VERSION 5.7 ;
  NOWIREEXTENSIONATPIN ON ;
  DIVIDERCHAR "/" ;
  BUSBITCHARS "[]" ;
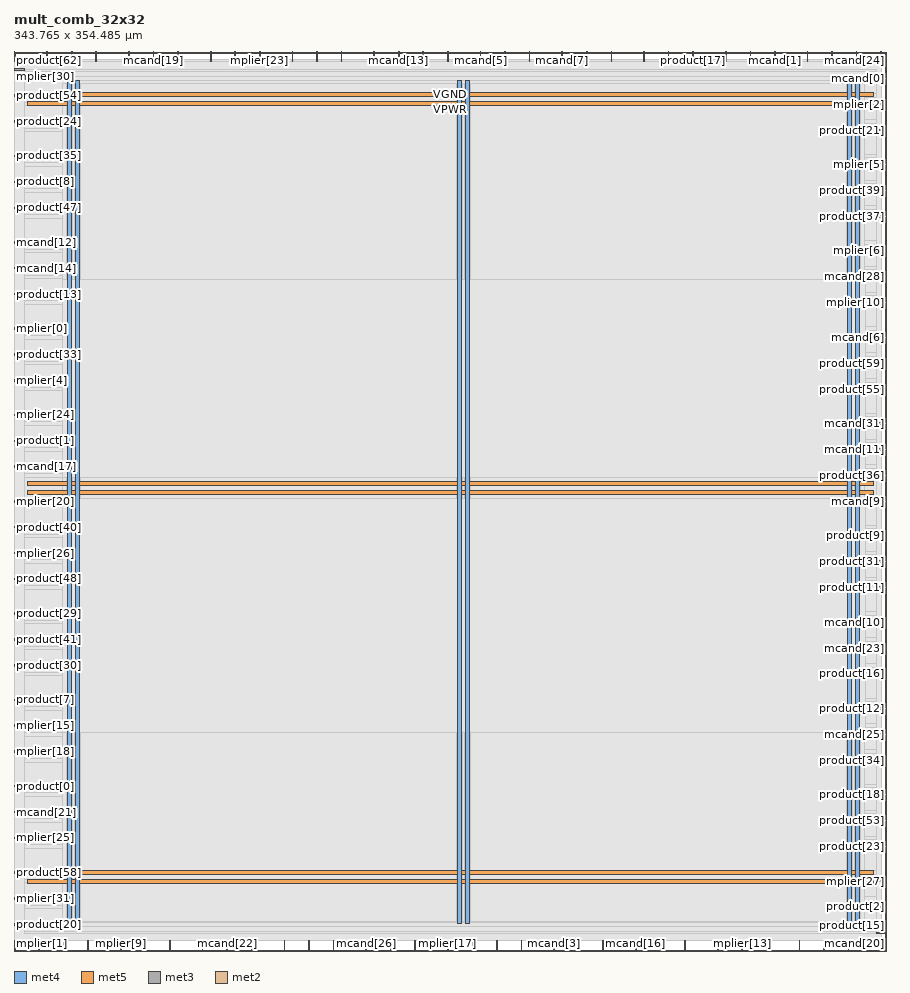
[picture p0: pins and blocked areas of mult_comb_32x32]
MACRO mult_comb_32x32
  CLASS BLOCK ;
  FOREIGN mult_comb_32x32 ;
  ORIGIN 0.000 0.000 ;
  SIZE 343.765 BY 354.485 ;
  PIN VGND
    DIRECTION INOUT ;
    USE GROUND ;
    PORT
      LAYER met4 ;
        RECT 24.340 10.640 25.940 342.960 ;
    END
    PORT
      LAYER met4 ;
        RECT 177.940 10.640 179.540 342.960 ;
    END
    PORT
      LAYER met4 ;
        RECT 331.540 10.640 333.140 342.960 ;
    END
    PORT
      LAYER met5 ;
        RECT 5.280 30.030 338.340 31.630 ;
    END
    PORT
      LAYER met5 ;
        RECT 5.280 183.210 338.340 184.810 ;
    END
    PORT
      LAYER met5 ;
        RECT 5.280 336.390 338.340 337.990 ;
    END
  END VGND
  PIN VPWR
    DIRECTION INOUT ;
    USE POWER ;
    PORT
      LAYER met4 ;
        RECT 21.040 10.640 22.640 342.960 ;
    END
    PORT
      LAYER met4 ;
        RECT 174.640 10.640 176.240 342.960 ;
    END
    PORT
      LAYER met4 ;
        RECT 328.240 10.640 329.840 342.960 ;
    END
    PORT
      LAYER met5 ;
        RECT 5.280 26.730 338.340 28.330 ;
    END
    PORT
      LAYER met5 ;
        RECT 5.280 179.910 338.340 181.510 ;
    END
    PORT
      LAYER met5 ;
        RECT 5.280 333.090 338.340 334.690 ;
    END
  END VPWR
  PIN mcand[0]
    DIRECTION INPUT ;
    USE SIGNAL ;
    ANTENNAGATEAREA 0.426000 ;
    PORT
      LAYER met3 ;
        RECT 339.765 343.440 343.765 344.040 ;
    END
  END mcand[0]
  PIN mcand[10]
    DIRECTION INPUT ;
    USE SIGNAL ;
    ANTENNAGATEAREA 0.159000 ;
    PORT
      LAYER met3 ;
        RECT 339.765 129.240 343.765 129.840 ;
    END
  END mcand[10]
  PIN mcand[11]
    DIRECTION INPUT ;
    USE SIGNAL ;
    ANTENNAGATEAREA 0.247500 ;
    PORT
      LAYER met3 ;
        RECT 339.765 197.240 343.765 197.840 ;
    END
  END mcand[11]
  PIN mcand[12]
    DIRECTION INPUT ;
    USE SIGNAL ;
    ANTENNAGATEAREA 0.213000 ;
    PORT
      LAYER met3 ;
        RECT 0.000 278.840 4.000 279.440 ;
    END
  END mcand[12]
  PIN mcand[13]
    DIRECTION INPUT ;
    USE SIGNAL ;
    ANTENNAGATEAREA 0.247500 ;
    PORT
      LAYER met2 ;
        RECT 151.430 350.485 151.710 354.485 ;
    END
  END mcand[13]
  PIN mcand[14]
    DIRECTION INPUT ;
    USE SIGNAL ;
    ANTENNAGATEAREA 0.247500 ;
    PORT
      LAYER met3 ;
        RECT 0.000 268.640 4.000 269.240 ;
    END
  END mcand[14]
  PIN mcand[15]
    DIRECTION INPUT ;
    USE SIGNAL ;
    ANTENNAGATEAREA 0.159000 ;
    PORT
      LAYER met2 ;
        RECT 161.090 350.485 161.370 354.485 ;
    END
  END mcand[15]
  PIN mcand[16]
    DIRECTION INPUT ;
    USE SIGNAL ;
    ANTENNAGATEAREA 0.213000 ;
    PORT
      LAYER met2 ;
        RECT 244.810 0.000 245.090 4.000 ;
    END
  END mcand[16]
  PIN mcand[17]
    DIRECTION INPUT ;
    USE SIGNAL ;
    ANTENNAGATEAREA 0.213000 ;
    PORT
      LAYER met3 ;
        RECT 0.000 190.440 4.000 191.040 ;
    END
  END mcand[17]
  PIN mcand[18]
    DIRECTION INPUT ;
    USE SIGNAL ;
    ANTENNAGATEAREA 0.247500 ;
    PORT
      LAYER met2 ;
        RECT 289.890 350.485 290.170 354.485 ;
    END
  END mcand[18]
  PIN mcand[19]
    DIRECTION INPUT ;
    USE SIGNAL ;
    ANTENNAGATEAREA 0.247500 ;
    PORT
      LAYER met2 ;
        RECT 54.830 350.485 55.110 354.485 ;
    END
  END mcand[19]
  PIN mcand[1]
    DIRECTION INPUT ;
    USE SIGNAL ;
    ANTENNAGATEAREA 0.159000 ;
    PORT
      LAYER met2 ;
        RECT 299.550 350.485 299.830 354.485 ;
    END
  END mcand[1]
  PIN mcand[20]
    DIRECTION INPUT ;
    USE SIGNAL ;
    ANTENNAGATEAREA 0.247500 ;
    PORT
      LAYER met2 ;
        RECT 341.410 0.000 341.690 4.000 ;
    END
  END mcand[20]
  PIN mcand[21]
    DIRECTION INPUT ;
    USE SIGNAL ;
    ANTENNAGATEAREA 0.213000 ;
    PORT
      LAYER met3 ;
        RECT 0.000 54.440 4.000 55.040 ;
    END
  END mcand[21]
  PIN mcand[22]
    DIRECTION INPUT ;
    USE SIGNAL ;
    ANTENNAGATEAREA 0.213000 ;
    PORT
      LAYER met2 ;
        RECT 83.810 0.000 84.090 4.000 ;
    END
  END mcand[22]
  PIN mcand[23]
    DIRECTION INPUT ;
    USE SIGNAL ;
    ANTENNAGATEAREA 0.213000 ;
    PORT
      LAYER met3 ;
        RECT 339.765 119.040 343.765 119.640 ;
    END
  END mcand[23]
  PIN mcand[24]
    DIRECTION INPUT ;
    USE SIGNAL ;
    ANTENNAGATEAREA 0.247500 ;
    PORT
      LAYER met2 ;
        RECT 341.410 350.485 341.690 354.485 ;
    END
  END mcand[24]
  PIN mcand[25]
    DIRECTION INPUT ;
    USE SIGNAL ;
    ANTENNAGATEAREA 0.159000 ;
    PORT
      LAYER met3 ;
        RECT 339.765 85.040 343.765 85.640 ;
    END
  END mcand[25]
  PIN mcand[26]
    DIRECTION INPUT ;
    USE SIGNAL ;
    ANTENNAGATEAREA 0.247500 ;
    PORT
      LAYER met2 ;
        RECT 138.550 0.000 138.830 4.000 ;
    END
  END mcand[26]
  PIN mcand[27]
    DIRECTION INPUT ;
    USE SIGNAL ;
    ANTENNAGATEAREA 0.159000 ;
    PORT
      LAYER met2 ;
        RECT 141.770 350.485 142.050 354.485 ;
    END
  END mcand[27]
  PIN mcand[28]
    DIRECTION INPUT ;
    USE SIGNAL ;
    ANTENNAGATEAREA 0.213000 ;
    PORT
      LAYER met3 ;
        RECT 339.765 265.240 343.765 265.840 ;
    END
  END mcand[28]
  PIN mcand[29]
    DIRECTION INPUT ;
    USE SIGNAL ;
    ANTENNAGATEAREA 0.247500 ;
    PORT
      LAYER met2 ;
        RECT 199.730 0.000 200.010 4.000 ;
    END
  END mcand[29]
  PIN mcand[2]
    DIRECTION INPUT ;
    USE SIGNAL ;
    ANTENNAGATEAREA 0.196500 ;
    PORT
      LAYER met2 ;
        RECT 93.470 0.000 93.750 4.000 ;
    END
  END mcand[2]
  PIN mcand[30]
    DIRECTION INPUT ;
    USE SIGNAL ;
    ANTENNAGATEAREA 0.196500 ;
    PORT
      LAYER met2 ;
        RECT 77.370 350.485 77.650 354.485 ;
    END
  END mcand[30]
  PIN mcand[31]
    DIRECTION INPUT ;
    USE SIGNAL ;
    ANTENNAGATEAREA 0.196500 ;
    PORT
      LAYER met3 ;
        RECT 339.765 207.440 343.765 208.040 ;
    END
  END mcand[31]
  PIN mcand[3]
    DIRECTION INPUT ;
    USE SIGNAL ;
    ANTENNAGATEAREA 0.196500 ;
    PORT
      LAYER met2 ;
        RECT 212.610 0.000 212.890 4.000 ;
    END
  END mcand[3]
  PIN mcand[4]
    DIRECTION INPUT ;
    USE SIGNAL ;
    ANTENNAGATEAREA 0.426000 ;
    PORT
      LAYER met2 ;
        RECT 322.090 350.485 322.370 354.485 ;
    END
  END mcand[4]
  PIN mcand[5]
    DIRECTION INPUT ;
    USE SIGNAL ;
    ANTENNAGATEAREA 0.213000 ;
    PORT
      LAYER met2 ;
        RECT 183.630 350.485 183.910 354.485 ;
    END
  END mcand[5]
  PIN mcand[6]
    DIRECTION INPUT ;
    USE SIGNAL ;
    ANTENNAGATEAREA 0.213000 ;
    PORT
      LAYER met3 ;
        RECT 339.765 241.440 343.765 242.040 ;
    END
  END mcand[6]
  PIN mcand[7]
    DIRECTION INPUT ;
    USE SIGNAL ;
    ANTENNAGATEAREA 0.213000 ;
    PORT
      LAYER met2 ;
        RECT 215.830 350.485 216.110 354.485 ;
    END
  END mcand[7]
  PIN mcand[8]
    DIRECTION INPUT ;
    USE SIGNAL ;
    ANTENNAGATEAREA 0.247500 ;
    PORT
      LAYER met2 ;
        RECT 328.530 0.000 328.810 4.000 ;
    END
  END mcand[8]
  PIN mcand[9]
    DIRECTION INPUT ;
    USE SIGNAL ;
    ANTENNAGATEAREA 0.213000 ;
    PORT
      LAYER met3 ;
        RECT 339.765 176.840 343.765 177.440 ;
    END
  END mcand[9]
  PIN mplier[0]
    DIRECTION INPUT ;
    USE SIGNAL ;
    ANTENNAGATEAREA 0.213000 ;
    PORT
      LAYER met3 ;
        RECT 0.000 244.840 4.000 245.440 ;
    END
  END mplier[0]
  PIN mplier[10]
    DIRECTION INPUT ;
    USE SIGNAL ;
    ANTENNAGATEAREA 0.247500 ;
    PORT
      LAYER met3 ;
        RECT 339.765 255.040 343.765 255.640 ;
    END
  END mplier[10]
  PIN mplier[11]
    DIRECTION INPUT ;
    USE SIGNAL ;
    ANTENNAGATEAREA 0.213000 ;
    PORT
      LAYER met2 ;
        RECT 148.210 0.000 148.490 4.000 ;
    END
  END mplier[11]
  PIN mplier[12]
    DIRECTION INPUT ;
    USE SIGNAL ;
    ANTENNAGATEAREA 0.213000 ;
    PORT
      LAYER met2 ;
        RECT 331.750 350.485 332.030 354.485 ;
    END
  END mplier[12]
  PIN mplier[13]
    DIRECTION INPUT ;
    USE SIGNAL ;
    ANTENNAGATEAREA 0.247500 ;
    PORT
      LAYER met2 ;
        RECT 286.670 0.000 286.950 4.000 ;
    END
  END mplier[13]
  PIN mplier[14]
    DIRECTION INPUT ;
    USE SIGNAL ;
    ANTENNAGATEAREA 0.213000 ;
    PORT
      LAYER met2 ;
        RECT 264.130 0.000 264.410 4.000 ;
    END
  END mplier[14]
  PIN mplier[15]
    DIRECTION INPUT ;
    USE SIGNAL ;
    ANTENNAGATEAREA 0.196500 ;
    PORT
      LAYER met3 ;
        RECT 0.000 88.440 4.000 89.040 ;
    END
  END mplier[15]
  PIN mplier[16]
    DIRECTION INPUT ;
    USE SIGNAL ;
    ANTENNAGATEAREA 0.213000 ;
    PORT
      LAYER met2 ;
        RECT 106.350 0.000 106.630 4.000 ;
    END
  END mplier[16]
  PIN mplier[17]
    DIRECTION INPUT ;
    USE SIGNAL ;
    ANTENNAGATEAREA 0.159000 ;
    PORT
      LAYER met2 ;
        RECT 170.750 0.000 171.030 4.000 ;
    END
  END mplier[17]
  PIN mplier[18]
    DIRECTION INPUT ;
    USE SIGNAL ;
    ANTENNAGATEAREA 0.213000 ;
    PORT
      LAYER met3 ;
        RECT 0.000 78.240 4.000 78.840 ;
    END
  END mplier[18]
  PIN mplier[19]
    DIRECTION INPUT ;
    USE SIGNAL ;
    ANTENNAGATEAREA 0.247500 ;
    PORT
      LAYER met2 ;
        RECT 193.290 350.485 193.570 354.485 ;
    END
  END mplier[19]
  PIN mplier[1]
    DIRECTION INPUT ;
    USE SIGNAL ;
    ANTENNAGATEAREA 0.159000 ;
    PORT
      LAYER met2 ;
        RECT 9.750 0.000 10.030 4.000 ;
    END
  END mplier[1]
  PIN mplier[20]
    DIRECTION INPUT ;
    USE SIGNAL ;
    ANTENNAGATEAREA 0.213000 ;
    PORT
      LAYER met3 ;
        RECT 0.000 176.840 4.000 177.440 ;
    END
  END mplier[20]
  PIN mplier[21]
    DIRECTION INPUT ;
    USE SIGNAL ;
    ANTENNAGATEAREA 0.213000 ;
    PORT
      LAYER met2 ;
        RECT 32.290 350.485 32.570 354.485 ;
    END
  END mplier[21]
  PIN mplier[22]
    DIRECTION INPUT ;
    USE SIGNAL ;
    ANTENNAGATEAREA 0.213000 ;
    PORT
      LAYER met2 ;
        RECT 235.150 350.485 235.430 354.485 ;
    END
  END mplier[22]
  PIN mplier[23]
    DIRECTION INPUT ;
    USE SIGNAL ;
    ANTENNAGATEAREA 0.159000 ;
    PORT
      LAYER met2 ;
        RECT 96.690 350.485 96.970 354.485 ;
    END
  END mplier[23]
  PIN mplier[24]
    DIRECTION INPUT ;
    USE SIGNAL ;
    ANTENNAGATEAREA 0.213000 ;
    PORT
      LAYER met3 ;
        RECT 0.000 210.840 4.000 211.440 ;
    END
  END mplier[24]
  PIN mplier[25]
    DIRECTION INPUT ;
    USE SIGNAL ;
    ANTENNAGATEAREA 0.126000 ;
    PORT
      LAYER met3 ;
        RECT 0.000 44.240 4.000 44.840 ;
    END
  END mplier[25]
  PIN mplier[26]
    DIRECTION INPUT ;
    USE SIGNAL ;
    ANTENNAGATEAREA 0.159000 ;
    PORT
      LAYER met3 ;
        RECT 0.000 156.440 4.000 157.040 ;
    END
  END mplier[26]
  PIN mplier[27]
    DIRECTION INPUT ;
    USE SIGNAL ;
    ANTENNAGATEAREA 0.213000 ;
    PORT
      LAYER met3 ;
        RECT 339.765 27.240 343.765 27.840 ;
    END
  END mplier[27]
  PIN mplier[28]
    DIRECTION INPUT ;
    USE SIGNAL ;
    ANTENNAGATEAREA 0.213000 ;
    PORT
      LAYER met2 ;
        RECT 125.670 0.000 125.950 4.000 ;
    END
  END mplier[28]
  PIN mplier[29]
    DIRECTION INPUT ;
    USE SIGNAL ;
    ANTENNAGATEAREA 0.126000 ;
    PORT
      LAYER met2 ;
        RECT 51.610 0.000 51.890 4.000 ;
    END
  END mplier[29]
  PIN mplier[2]
    DIRECTION INPUT ;
    USE SIGNAL ;
    ANTENNAGATEAREA 0.247500 ;
    PORT
      LAYER met3 ;
        RECT 339.765 333.240 343.765 333.840 ;
    END
  END mplier[2]
  PIN mplier[30]
    DIRECTION INPUT ;
    USE SIGNAL ;
    ANTENNAGATEAREA 0.159000 ;
    PORT
      LAYER met3 ;
        RECT 0.000 346.840 4.000 347.440 ;
    END
  END mplier[30]
  PIN mplier[31]
    DIRECTION INPUT ;
    USE SIGNAL ;
    ANTENNAGATEAREA 0.213000 ;
    PORT
      LAYER met3 ;
        RECT 0.000 20.440 4.000 21.040 ;
    END
  END mplier[31]
  PIN mplier[3]
    DIRECTION INPUT ;
    USE SIGNAL ;
    ANTENNAGATEAREA 0.213000 ;
    PORT
      LAYER met2 ;
        RECT 87.030 350.485 87.310 354.485 ;
    END
  END mplier[3]
  PIN mplier[4]
    DIRECTION INPUT ;
    USE SIGNAL ;
    ANTENNAGATEAREA 0.159000 ;
    PORT
      LAYER met3 ;
        RECT 0.000 224.440 4.000 225.040 ;
    END
  END mplier[4]
  PIN mplier[5]
    DIRECTION INPUT ;
    USE SIGNAL ;
    ANTENNAGATEAREA 0.159000 ;
    PORT
      LAYER met3 ;
        RECT 339.765 309.440 343.765 310.040 ;
    END
  END mplier[5]
  PIN mplier[6]
    DIRECTION INPUT ;
    USE SIGNAL ;
    ANTENNAGATEAREA 0.213000 ;
    PORT
      LAYER met3 ;
        RECT 339.765 275.440 343.765 276.040 ;
    END
  END mplier[6]
  PIN mplier[7]
    DIRECTION INPUT ;
    USE SIGNAL ;
    ANTENNAGATEAREA 0.247500 ;
    PORT
      LAYER met2 ;
        RECT 22.630 350.485 22.910 354.485 ;
    END
  END mplier[7]
  PIN mplier[8]
    DIRECTION INPUT ;
    USE SIGNAL ;
    ANTENNAGATEAREA 0.159000 ;
    PORT
      LAYER met2 ;
        RECT 45.170 350.485 45.450 354.485 ;
    END
  END mplier[8]
  PIN mplier[9]
    DIRECTION INPUT ;
    USE SIGNAL ;
    ANTENNAGATEAREA 0.213000 ;
    PORT
      LAYER met2 ;
        RECT 41.950 0.000 42.230 4.000 ;
    END
  END mplier[9]
  PIN product[0]
    DIRECTION OUTPUT TRISTATE ;
    USE SIGNAL ;
    ANTENNADIFFAREA 0.795200 ;
    PORT
      LAYER met3 ;
        RECT 0.000 64.640 4.000 65.240 ;
    END
  END product[0]
  PIN product[10]
    DIRECTION OUTPUT TRISTATE ;
    USE SIGNAL ;
    ANTENNADIFFAREA 0.795200 ;
    PORT
      LAYER met2 ;
        RECT 119.230 350.485 119.510 354.485 ;
    END
  END product[10]
  PIN product[11]
    DIRECTION OUTPUT TRISTATE ;
    USE SIGNAL ;
    ANTENNADIFFAREA 0.795200 ;
    PORT
      LAYER met3 ;
        RECT 339.765 142.840 343.765 143.440 ;
    END
  END product[11]
  PIN product[12]
    DIRECTION OUTPUT TRISTATE ;
    USE SIGNAL ;
    ANTENNADIFFAREA 0.795200 ;
    PORT
      LAYER met3 ;
        RECT 339.765 95.240 343.765 95.840 ;
    END
  END product[12]
  PIN product[13]
    DIRECTION OUTPUT TRISTATE ;
    USE SIGNAL ;
    ANTENNADIFFAREA 0.795200 ;
    PORT
      LAYER met3 ;
        RECT 0.000 258.440 4.000 259.040 ;
    END
  END product[13]
  PIN product[14]
    DIRECTION OUTPUT TRISTATE ;
    USE SIGNAL ;
    ANTENNADIFFAREA 0.795200 ;
    PORT
      LAYER met2 ;
        RECT 128.890 350.485 129.170 354.485 ;
    END
  END product[14]
  PIN product[15]
    DIRECTION OUTPUT TRISTATE ;
    USE SIGNAL ;
    ANTENNADIFFAREA 0.445500 ;
    PORT
      LAYER met3 ;
        RECT 339.765 6.840 343.765 7.440 ;
    END
  END product[15]
  PIN product[16]
    DIRECTION OUTPUT TRISTATE ;
    USE SIGNAL ;
    ANTENNADIFFAREA 0.445500 ;
    PORT
      LAYER met3 ;
        RECT 339.765 108.840 343.765 109.440 ;
    END
  END product[16]
  PIN product[17]
    DIRECTION OUTPUT TRISTATE ;
    USE SIGNAL ;
    ANTENNADIFFAREA 0.795200 ;
    PORT
      LAYER met2 ;
        RECT 267.350 350.485 267.630 354.485 ;
    END
  END product[17]
  PIN product[18]
    DIRECTION OUTPUT TRISTATE ;
    USE SIGNAL ;
    ANTENNADIFFAREA 0.795200 ;
    PORT
      LAYER met3 ;
        RECT 339.765 61.240 343.765 61.840 ;
    END
  END product[18]
  PIN product[19]
    DIRECTION OUTPUT TRISTATE ;
    USE SIGNAL ;
    ANTENNADIFFAREA 0.795200 ;
    PORT
      LAYER met2 ;
        RECT 296.330 0.000 296.610 4.000 ;
    END
  END product[19]
  PIN product[1]
    DIRECTION OUTPUT TRISTATE ;
    USE SIGNAL ;
    ANTENNADIFFAREA 0.795200 ;
    PORT
      LAYER met3 ;
        RECT 0.000 200.640 4.000 201.240 ;
    END
  END product[1]
  PIN product[20]
    DIRECTION OUTPUT TRISTATE ;
    USE SIGNAL ;
    ANTENNADIFFAREA 0.795200 ;
    PORT
      LAYER met3 ;
        RECT 0.000 10.240 4.000 10.840 ;
    END
  END product[20]
  PIN product[21]
    DIRECTION OUTPUT TRISTATE ;
    USE SIGNAL ;
    ANTENNADIFFAREA 0.795200 ;
    PORT
      LAYER met3 ;
        RECT 339.765 323.040 343.765 323.640 ;
    END
  END product[21]
  PIN product[22]
    DIRECTION OUTPUT TRISTATE ;
    USE SIGNAL ;
    ANTENNADIFFAREA 0.795200 ;
    PORT
      LAYER met2 ;
        RECT 74.150 0.000 74.430 4.000 ;
    END
  END product[22]
  PIN product[23]
    DIRECTION OUTPUT TRISTATE ;
    USE SIGNAL ;
    ANTENNADIFFAREA 0.795200 ;
    PORT
      LAYER met3 ;
        RECT 339.765 40.840 343.765 41.440 ;
    END
  END product[23]
  PIN product[24]
    DIRECTION OUTPUT TRISTATE ;
    USE SIGNAL ;
    ANTENNADIFFAREA 0.795200 ;
    PORT
      LAYER met3 ;
        RECT 0.000 326.440 4.000 327.040 ;
    END
  END product[24]
  PIN product[25]
    DIRECTION OUTPUT TRISTATE ;
    USE SIGNAL ;
    ANTENNADIFFAREA 0.795200 ;
    PORT
      LAYER met2 ;
        RECT 318.870 0.000 319.150 4.000 ;
    END
  END product[25]
  PIN product[26]
    DIRECTION OUTPUT TRISTATE ;
    USE SIGNAL ;
    ANTENNADIFFAREA 0.795200 ;
    PORT
      LAYER met2 ;
        RECT 170.750 350.485 171.030 354.485 ;
    END
  END product[26]
  PIN product[27]
    DIRECTION OUTPUT TRISTATE ;
    USE SIGNAL ;
    ANTENNADIFFAREA 0.795200 ;
    PORT
      LAYER met2 ;
        RECT 254.470 0.000 254.750 4.000 ;
    END
  END product[27]
  PIN product[28]
    DIRECTION OUTPUT TRISTATE ;
    USE SIGNAL ;
    ANTENNADIFFAREA 0.795200 ;
    PORT
      LAYER met2 ;
        RECT 29.070 0.000 29.350 4.000 ;
    END
  END product[28]
  PIN product[29]
    DIRECTION OUTPUT TRISTATE ;
    USE SIGNAL ;
    ANTENNADIFFAREA 0.795200 ;
    PORT
      LAYER met3 ;
        RECT 0.000 132.640 4.000 133.240 ;
    END
  END product[29]
  PIN product[2]
    DIRECTION OUTPUT TRISTATE ;
    USE SIGNAL ;
    ANTENNADIFFAREA 0.445500 ;
    PORT
      LAYER met3 ;
        RECT 339.765 17.040 343.765 17.640 ;
    END
  END product[2]
  PIN product[30]
    DIRECTION OUTPUT TRISTATE ;
    USE SIGNAL ;
    ANTENNADIFFAREA 0.795200 ;
    PORT
      LAYER met3 ;
        RECT 0.000 112.240 4.000 112.840 ;
    END
  END product[30]
  PIN product[31]
    DIRECTION OUTPUT TRISTATE ;
    USE SIGNAL ;
    ANTENNADIFFAREA 0.445500 ;
    PORT
      LAYER met3 ;
        RECT 339.765 153.040 343.765 153.640 ;
    END
  END product[31]
  PIN product[32]
    DIRECTION OUTPUT TRISTATE ;
    USE SIGNAL ;
    ANTENNADIFFAREA 0.795200 ;
    PORT
      LAYER met2 ;
        RECT 277.010 0.000 277.290 4.000 ;
    END
  END product[32]
  PIN product[33]
    DIRECTION OUTPUT TRISTATE ;
    USE SIGNAL ;
    ANTENNADIFFAREA 0.795200 ;
    PORT
      LAYER met3 ;
        RECT 0.000 234.640 4.000 235.240 ;
    END
  END product[33]
  PIN product[34]
    DIRECTION OUTPUT TRISTATE ;
    USE SIGNAL ;
    ANTENNADIFFAREA 0.795200 ;
    PORT
      LAYER met3 ;
        RECT 339.765 74.840 343.765 75.440 ;
    END
  END product[34]
  PIN product[35]
    DIRECTION OUTPUT TRISTATE ;
    USE SIGNAL ;
    ANTENNADIFFAREA 0.795200 ;
    PORT
      LAYER met3 ;
        RECT 0.000 312.840 4.000 313.440 ;
    END
  END product[35]
  PIN product[36]
    DIRECTION OUTPUT TRISTATE ;
    USE SIGNAL ;
    ANTENNADIFFAREA 0.445500 ;
    PORT
      LAYER met3 ;
        RECT 339.765 187.040 343.765 187.640 ;
    END
  END product[36]
  PIN product[37]
    DIRECTION OUTPUT TRISTATE ;
    USE SIGNAL ;
    ANTENNADIFFAREA 0.445500 ;
    PORT
      LAYER met3 ;
        RECT 339.765 289.040 343.765 289.640 ;
    END
  END product[37]
  PIN product[38]
    DIRECTION OUTPUT TRISTATE ;
    USE SIGNAL ;
    ANTENNADIFFAREA 0.795200 ;
    PORT
      LAYER met2 ;
        RECT 309.210 0.000 309.490 4.000 ;
    END
  END product[38]
  PIN product[39]
    DIRECTION OUTPUT TRISTATE ;
    USE SIGNAL ;
    ANTENNADIFFAREA 0.445500 ;
    PORT
      LAYER met3 ;
        RECT 339.765 299.240 343.765 299.840 ;
    END
  END product[39]
  PIN product[3]
    DIRECTION OUTPUT TRISTATE ;
    USE SIGNAL ;
    ANTENNADIFFAREA 0.795200 ;
    PORT
      LAYER met2 ;
        RECT 180.410 0.000 180.690 4.000 ;
    END
  END product[3]
  PIN product[40]
    DIRECTION OUTPUT TRISTATE ;
    USE SIGNAL ;
    ANTENNADIFFAREA 0.795200 ;
    PORT
      LAYER met3 ;
        RECT 0.000 166.640 4.000 167.240 ;
    END
  END product[40]
  PIN product[41]
    DIRECTION OUTPUT TRISTATE ;
    USE SIGNAL ;
    ANTENNADIFFAREA 0.795200 ;
    PORT
      LAYER met3 ;
        RECT 0.000 122.440 4.000 123.040 ;
    END
  END product[41]
  PIN product[42]
    DIRECTION OUTPUT TRISTATE ;
    USE SIGNAL ;
    ANTENNADIFFAREA 0.795200 ;
    PORT
      LAYER met2 ;
        RECT 0.090 0.000 0.370 4.000 ;
    END
  END product[42]
  PIN product[43]
    DIRECTION OUTPUT TRISTATE ;
    USE SIGNAL ;
    ANTENNADIFFAREA 0.795200 ;
    PORT
      LAYER met2 ;
        RECT 222.270 0.000 222.550 4.000 ;
    END
  END product[43]
  PIN product[44]
    DIRECTION OUTPUT TRISTATE ;
    USE SIGNAL ;
    ANTENNADIFFAREA 0.795200 ;
    PORT
      LAYER met2 ;
        RECT 0.090 350.485 0.370 354.485 ;
    END
  END product[44]
  PIN product[45]
    DIRECTION OUTPUT TRISTATE ;
    USE SIGNAL ;
    ANTENNADIFFAREA 0.795200 ;
    PORT
      LAYER met2 ;
        RECT 109.570 350.485 109.850 354.485 ;
    END
  END product[45]
  PIN product[46]
    DIRECTION OUTPUT TRISTATE ;
    USE SIGNAL ;
    ANTENNADIFFAREA 0.795200 ;
    PORT
      LAYER met2 ;
        RECT 225.490 350.485 225.770 354.485 ;
    END
  END product[46]
  PIN product[47]
    DIRECTION OUTPUT TRISTATE ;
    USE SIGNAL ;
    ANTENNADIFFAREA 0.795200 ;
    PORT
      LAYER met3 ;
        RECT 0.000 292.440 4.000 293.040 ;
    END
  END product[47]
  PIN product[48]
    DIRECTION OUTPUT TRISTATE ;
    USE SIGNAL ;
    ANTENNADIFFAREA 0.795200 ;
    PORT
      LAYER met3 ;
        RECT 0.000 146.240 4.000 146.840 ;
    END
  END product[48]
  PIN product[49]
    DIRECTION OUTPUT TRISTATE ;
    USE SIGNAL ;
    ANTENNADIFFAREA 0.795200 ;
    PORT
      LAYER met2 ;
        RECT 19.410 0.000 19.690 4.000 ;
    END
  END product[49]
  PIN product[4]
    DIRECTION OUTPUT TRISTATE ;
    USE SIGNAL ;
    ANTENNADIFFAREA 0.795200 ;
    PORT
      LAYER met2 ;
        RECT 280.230 350.485 280.510 354.485 ;
    END
  END product[4]
  PIN product[50]
    DIRECTION OUTPUT TRISTATE ;
    USE SIGNAL ;
    ANTENNADIFFAREA 0.445500 ;
    PORT
      LAYER met2 ;
        RECT 202.950 350.485 203.230 354.485 ;
    END
  END product[50]
  PIN product[51]
    DIRECTION OUTPUT TRISTATE ;
    USE SIGNAL ;
    ANTENNADIFFAREA 0.795200 ;
    PORT
      LAYER met2 ;
        RECT 157.870 0.000 158.150 4.000 ;
    END
  END product[51]
  PIN product[52]
    DIRECTION OUTPUT TRISTATE ;
    USE SIGNAL ;
    ANTENNADIFFAREA 0.795200 ;
    PORT
      LAYER met2 ;
        RECT 312.430 350.485 312.710 354.485 ;
    END
  END product[52]
  PIN product[53]
    DIRECTION OUTPUT TRISTATE ;
    USE SIGNAL ;
    ANTENNADIFFAREA 0.445500 ;
    PORT
      LAYER met3 ;
        RECT 339.765 51.040 343.765 51.640 ;
    END
  END product[53]
  PIN product[54]
    DIRECTION OUTPUT TRISTATE ;
    USE SIGNAL ;
    ANTENNADIFFAREA 0.795200 ;
    PORT
      LAYER met3 ;
        RECT 0.000 336.640 4.000 337.240 ;
    END
  END product[54]
  PIN product[55]
    DIRECTION OUTPUT TRISTATE ;
    USE SIGNAL ;
    ANTENNADIFFAREA 0.445500 ;
    PORT
      LAYER met3 ;
        RECT 339.765 221.040 343.765 221.640 ;
    END
  END product[55]
  PIN product[56]
    DIRECTION OUTPUT TRISTATE ;
    USE SIGNAL ;
    ANTENNADIFFAREA 0.795200 ;
    PORT
      LAYER met2 ;
        RECT 61.270 0.000 61.550 4.000 ;
    END
  END product[56]
  PIN product[57]
    DIRECTION OUTPUT TRISTATE ;
    USE SIGNAL ;
    ANTENNADIFFAREA 0.795200 ;
    PORT
      LAYER met2 ;
        RECT 116.010 0.000 116.290 4.000 ;
    END
  END product[57]
  PIN product[58]
    DIRECTION OUTPUT TRISTATE ;
    USE SIGNAL ;
    ANTENNADIFFAREA 0.795200 ;
    PORT
      LAYER met3 ;
        RECT 0.000 30.640 4.000 31.240 ;
    END
  END product[58]
  PIN product[59]
    DIRECTION OUTPUT TRISTATE ;
    USE SIGNAL ;
    ANTENNADIFFAREA 0.445500 ;
    PORT
      LAYER met3 ;
        RECT 339.765 231.240 343.765 231.840 ;
    END
  END product[59]
  PIN product[5]
    DIRECTION OUTPUT TRISTATE ;
    USE SIGNAL ;
    ANTENNADIFFAREA 0.795200 ;
    PORT
      LAYER met2 ;
        RECT 190.070 0.000 190.350 4.000 ;
    END
  END product[5]
  PIN product[60]
    DIRECTION OUTPUT TRISTATE ;
    USE SIGNAL ;
    ANTENNADIFFAREA 0.445500 ;
    PORT
      LAYER met2 ;
        RECT 257.690 350.485 257.970 354.485 ;
    END
  END product[60]
  PIN product[61]
    DIRECTION OUTPUT TRISTATE ;
    USE SIGNAL ;
    ANTENNADIFFAREA 0.795200 ;
    PORT
      LAYER met2 ;
        RECT 248.030 350.485 248.310 354.485 ;
    END
  END product[61]
  PIN product[62]
    DIRECTION OUTPUT TRISTATE ;
    USE SIGNAL ;
    ANTENNADIFFAREA 0.795200 ;
    PORT
      LAYER met2 ;
        RECT 12.970 350.485 13.250 354.485 ;
    END
  END product[62]
  PIN product[63]
    DIRECTION OUTPUT TRISTATE ;
    USE SIGNAL ;
    ANTENNADIFFAREA 0.445500 ;
    PORT
      LAYER met2 ;
        RECT 64.490 350.485 64.770 354.485 ;
    END
  END product[63]
  PIN product[6]
    DIRECTION OUTPUT TRISTATE ;
    USE SIGNAL ;
    ANTENNADIFFAREA 0.795200 ;
    PORT
      LAYER met2 ;
        RECT 231.930 0.000 232.210 4.000 ;
    END
  END product[6]
  PIN product[7]
    DIRECTION OUTPUT TRISTATE ;
    USE SIGNAL ;
    ANTENNADIFFAREA 0.795200 ;
    PORT
      LAYER met3 ;
        RECT 0.000 98.640 4.000 99.240 ;
    END
  END product[7]
  PIN product[8]
    DIRECTION OUTPUT TRISTATE ;
    USE SIGNAL ;
    ANTENNADIFFAREA 0.795200 ;
    PORT
      LAYER met3 ;
        RECT 0.000 302.640 4.000 303.240 ;
    END
  END product[8]
  PIN product[9]
    DIRECTION OUTPUT TRISTATE ;
    USE SIGNAL ;
    ANTENNADIFFAREA 0.445500 ;
    PORT
      LAYER met3 ;
        RECT 339.765 163.240 343.765 163.840 ;
    END
  END product[9]
  OBS
      LAYER li1 ;
        RECT 5.520 10.795 338.100 342.805 ;
      LAYER met1 ;
        RECT 0.070 7.520 341.710 345.740 ;
      LAYER met2 ;
        RECT 0.650 350.205 12.690 351.290 ;
        RECT 13.530 350.205 22.350 351.290 ;
        RECT 23.190 350.205 32.010 351.290 ;
        RECT 32.850 350.205 44.890 351.290 ;
        RECT 45.730 350.205 54.550 351.290 ;
        RECT 55.390 350.205 64.210 351.290 ;
        RECT 65.050 350.205 77.090 351.290 ;
        RECT 77.930 350.205 86.750 351.290 ;
        RECT 87.590 350.205 96.410 351.290 ;
        RECT 97.250 350.205 109.290 351.290 ;
        RECT 110.130 350.205 118.950 351.290 ;
        RECT 119.790 350.205 128.610 351.290 ;
        RECT 129.450 350.205 141.490 351.290 ;
        RECT 142.330 350.205 151.150 351.290 ;
        RECT 151.990 350.205 160.810 351.290 ;
        RECT 161.650 350.205 170.470 351.290 ;
        RECT 171.310 350.205 183.350 351.290 ;
        RECT 184.190 350.205 193.010 351.290 ;
        RECT 193.850 350.205 202.670 351.290 ;
        RECT 203.510 350.205 215.550 351.290 ;
        RECT 216.390 350.205 225.210 351.290 ;
        RECT 226.050 350.205 234.870 351.290 ;
        RECT 235.710 350.205 247.750 351.290 ;
        RECT 248.590 350.205 257.410 351.290 ;
        RECT 258.250 350.205 267.070 351.290 ;
        RECT 267.910 350.205 279.950 351.290 ;
        RECT 280.790 350.205 289.610 351.290 ;
        RECT 290.450 350.205 299.270 351.290 ;
        RECT 300.110 350.205 312.150 351.290 ;
        RECT 312.990 350.205 321.810 351.290 ;
        RECT 322.650 350.205 331.470 351.290 ;
        RECT 332.310 350.205 341.130 351.290 ;
        RECT 0.100 4.280 341.680 350.205 ;
        RECT 0.650 4.000 9.470 4.280 ;
        RECT 10.310 4.000 19.130 4.280 ;
        RECT 19.970 4.000 28.790 4.280 ;
        RECT 29.630 4.000 41.670 4.280 ;
        RECT 42.510 4.000 51.330 4.280 ;
        RECT 52.170 4.000 60.990 4.280 ;
        RECT 61.830 4.000 73.870 4.280 ;
        RECT 74.710 4.000 83.530 4.280 ;
        RECT 84.370 4.000 93.190 4.280 ;
        RECT 94.030 4.000 106.070 4.280 ;
        RECT 106.910 4.000 115.730 4.280 ;
        RECT 116.570 4.000 125.390 4.280 ;
        RECT 126.230 4.000 138.270 4.280 ;
        RECT 139.110 4.000 147.930 4.280 ;
        RECT 148.770 4.000 157.590 4.280 ;
        RECT 158.430 4.000 170.470 4.280 ;
        RECT 171.310 4.000 180.130 4.280 ;
        RECT 180.970 4.000 189.790 4.280 ;
        RECT 190.630 4.000 199.450 4.280 ;
        RECT 200.290 4.000 212.330 4.280 ;
        RECT 213.170 4.000 221.990 4.280 ;
        RECT 222.830 4.000 231.650 4.280 ;
        RECT 232.490 4.000 244.530 4.280 ;
        RECT 245.370 4.000 254.190 4.280 ;
        RECT 255.030 4.000 263.850 4.280 ;
        RECT 264.690 4.000 276.730 4.280 ;
        RECT 277.570 4.000 286.390 4.280 ;
        RECT 287.230 4.000 296.050 4.280 ;
        RECT 296.890 4.000 308.930 4.280 ;
        RECT 309.770 4.000 318.590 4.280 ;
        RECT 319.430 4.000 328.250 4.280 ;
        RECT 329.090 4.000 341.130 4.280 ;
      LAYER met3 ;
        RECT 4.400 346.440 339.765 347.290 ;
        RECT 3.990 344.440 339.765 346.440 ;
        RECT 3.990 343.040 339.365 344.440 ;
        RECT 3.990 337.640 339.765 343.040 ;
        RECT 4.400 336.240 339.765 337.640 ;
        RECT 3.990 334.240 339.765 336.240 ;
        RECT 3.990 332.840 339.365 334.240 ;
        RECT 3.990 327.440 339.765 332.840 ;
        RECT 4.400 326.040 339.765 327.440 ;
        RECT 3.990 324.040 339.765 326.040 ;
        RECT 3.990 322.640 339.365 324.040 ;
        RECT 3.990 313.840 339.765 322.640 ;
        RECT 4.400 312.440 339.765 313.840 ;
        RECT 3.990 310.440 339.765 312.440 ;
        RECT 3.990 309.040 339.365 310.440 ;
        RECT 3.990 303.640 339.765 309.040 ;
        RECT 4.400 302.240 339.765 303.640 ;
        RECT 3.990 300.240 339.765 302.240 ;
        RECT 3.990 298.840 339.365 300.240 ;
        RECT 3.990 293.440 339.765 298.840 ;
        RECT 4.400 292.040 339.765 293.440 ;
        RECT 3.990 290.040 339.765 292.040 ;
        RECT 3.990 288.640 339.365 290.040 ;
        RECT 3.990 279.840 339.765 288.640 ;
        RECT 4.400 278.440 339.765 279.840 ;
        RECT 3.990 276.440 339.765 278.440 ;
        RECT 3.990 275.040 339.365 276.440 ;
        RECT 3.990 269.640 339.765 275.040 ;
        RECT 4.400 268.240 339.765 269.640 ;
        RECT 3.990 266.240 339.765 268.240 ;
        RECT 3.990 264.840 339.365 266.240 ;
        RECT 3.990 259.440 339.765 264.840 ;
        RECT 4.400 258.040 339.765 259.440 ;
        RECT 3.990 256.040 339.765 258.040 ;
        RECT 3.990 254.640 339.365 256.040 ;
        RECT 3.990 245.840 339.765 254.640 ;
        RECT 4.400 244.440 339.765 245.840 ;
        RECT 3.990 242.440 339.765 244.440 ;
        RECT 3.990 241.040 339.365 242.440 ;
        RECT 3.990 235.640 339.765 241.040 ;
        RECT 4.400 234.240 339.765 235.640 ;
        RECT 3.990 232.240 339.765 234.240 ;
        RECT 3.990 230.840 339.365 232.240 ;
        RECT 3.990 225.440 339.765 230.840 ;
        RECT 4.400 224.040 339.765 225.440 ;
        RECT 3.990 222.040 339.765 224.040 ;
        RECT 3.990 220.640 339.365 222.040 ;
        RECT 3.990 211.840 339.765 220.640 ;
        RECT 4.400 210.440 339.765 211.840 ;
        RECT 3.990 208.440 339.765 210.440 ;
        RECT 3.990 207.040 339.365 208.440 ;
        RECT 3.990 201.640 339.765 207.040 ;
        RECT 4.400 200.240 339.765 201.640 ;
        RECT 3.990 198.240 339.765 200.240 ;
        RECT 3.990 196.840 339.365 198.240 ;
        RECT 3.990 191.440 339.765 196.840 ;
        RECT 4.400 190.040 339.765 191.440 ;
        RECT 3.990 188.040 339.765 190.040 ;
        RECT 3.990 186.640 339.365 188.040 ;
        RECT 3.990 177.840 339.765 186.640 ;
        RECT 4.400 176.440 339.365 177.840 ;
        RECT 3.990 167.640 339.765 176.440 ;
        RECT 4.400 166.240 339.765 167.640 ;
        RECT 3.990 164.240 339.765 166.240 ;
        RECT 3.990 162.840 339.365 164.240 ;
        RECT 3.990 157.440 339.765 162.840 ;
        RECT 4.400 156.040 339.765 157.440 ;
        RECT 3.990 154.040 339.765 156.040 ;
        RECT 3.990 152.640 339.365 154.040 ;
        RECT 3.990 147.240 339.765 152.640 ;
        RECT 4.400 145.840 339.765 147.240 ;
        RECT 3.990 143.840 339.765 145.840 ;
        RECT 3.990 142.440 339.365 143.840 ;
        RECT 3.990 133.640 339.765 142.440 ;
        RECT 4.400 132.240 339.765 133.640 ;
        RECT 3.990 130.240 339.765 132.240 ;
        RECT 3.990 128.840 339.365 130.240 ;
        RECT 3.990 123.440 339.765 128.840 ;
        RECT 4.400 122.040 339.765 123.440 ;
        RECT 3.990 120.040 339.765 122.040 ;
        RECT 3.990 118.640 339.365 120.040 ;
        RECT 3.990 113.240 339.765 118.640 ;
        RECT 4.400 111.840 339.765 113.240 ;
        RECT 3.990 109.840 339.765 111.840 ;
        RECT 3.990 108.440 339.365 109.840 ;
        RECT 3.990 99.640 339.765 108.440 ;
        RECT 4.400 98.240 339.765 99.640 ;
        RECT 3.990 96.240 339.765 98.240 ;
        RECT 3.990 94.840 339.365 96.240 ;
        RECT 3.990 89.440 339.765 94.840 ;
        RECT 4.400 88.040 339.765 89.440 ;
        RECT 3.990 86.040 339.765 88.040 ;
        RECT 3.990 84.640 339.365 86.040 ;
        RECT 3.990 79.240 339.765 84.640 ;
        RECT 4.400 77.840 339.765 79.240 ;
        RECT 3.990 75.840 339.765 77.840 ;
        RECT 3.990 74.440 339.365 75.840 ;
        RECT 3.990 65.640 339.765 74.440 ;
        RECT 4.400 64.240 339.765 65.640 ;
        RECT 3.990 62.240 339.765 64.240 ;
        RECT 3.990 60.840 339.365 62.240 ;
        RECT 3.990 55.440 339.765 60.840 ;
        RECT 4.400 54.040 339.765 55.440 ;
        RECT 3.990 52.040 339.765 54.040 ;
        RECT 3.990 50.640 339.365 52.040 ;
        RECT 3.990 45.240 339.765 50.640 ;
        RECT 4.400 43.840 339.765 45.240 ;
        RECT 3.990 41.840 339.765 43.840 ;
        RECT 3.990 40.440 339.365 41.840 ;
        RECT 3.990 31.640 339.765 40.440 ;
        RECT 4.400 30.240 339.765 31.640 ;
        RECT 3.990 28.240 339.765 30.240 ;
        RECT 3.990 26.840 339.365 28.240 ;
        RECT 3.990 21.440 339.765 26.840 ;
        RECT 4.400 20.040 339.765 21.440 ;
        RECT 3.990 18.040 339.765 20.040 ;
        RECT 3.990 16.640 339.365 18.040 ;
        RECT 3.990 11.240 339.765 16.640 ;
        RECT 4.400 9.840 339.765 11.240 ;
        RECT 3.990 7.840 339.765 9.840 ;
        RECT 3.990 6.975 339.365 7.840 ;
      LAYER met4 ;
        RECT 19.190 11.735 20.640 341.865 ;
        RECT 23.040 11.735 23.940 341.865 ;
        RECT 26.340 11.735 174.240 341.865 ;
        RECT 176.640 11.735 177.540 341.865 ;
        RECT 179.940 11.735 327.840 341.865 ;
        RECT 330.240 11.735 331.140 341.865 ;
        RECT 333.540 11.735 335.010 341.865 ;
      LAYER met5 ;
        RECT 18.980 186.410 335.220 264.300 ;
        RECT 18.980 85.900 335.220 178.310 ;
  END
END mult_comb_32x32
END LIBRARY

